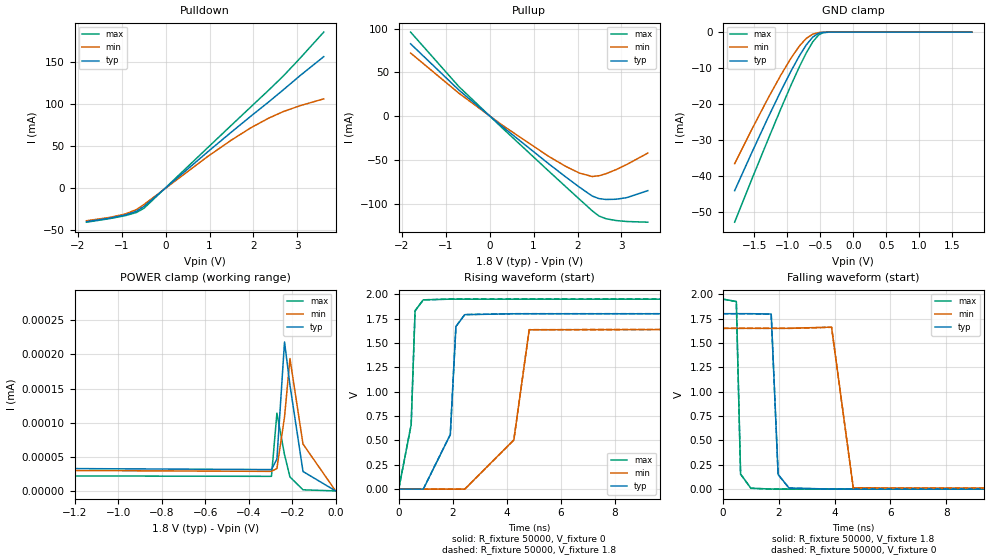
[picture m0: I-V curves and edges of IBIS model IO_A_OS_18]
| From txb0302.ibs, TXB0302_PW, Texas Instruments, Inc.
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[Model]   IO_A_OS_18
Model_type  3-state
Enable   Active-High
Vref =   0
Rref =   50000
Cref =   15p
Vmeas =   0.9
| variable   typ   min   max
C_comp   3.37pF   3.15pF   3.54pF
| C_pullup   1.07pF   0.66pF   1.90pF
| C_pulldown   0.87pF   0.62pF   1.33pF
| C_tri-state   3.37pF   3.15pF   3.54pF
[Temperature Range]   40   100   -40
| Ambient temperature   25   85   -40
[Voltage range]   1.8   1.65   1.95
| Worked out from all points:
|   slope of the pulldown table from 0 to 0.27 V, typ, clamps not added: 22.2 ohm
|   slope of the pullup table from 0 to 0.27 V, typ, clamps not added: 24.2 ohm
|   GND clamp passes 1 mA (typ) near -0.59 V on its own axis
|   rising waveform, R_fixture 50000, V_fixture 0: 20-80 % time 611ps typ, 1.04ns min, 363ps max; typ from 0 V to 1.8 V
|   falling waveform, R_fixture 50000, V_fixture 1.8: 20-80 % time 110ps typ, 174ps min, 69.9ps max; typ from 1.8 V to 0.001 V
|   rising waveform, R_fixture 50000, V_fixture 1.8: 20-80 % time 611ps typ, 1.04ns min, 363ps max; typ from 0.001 V to 1.8 V
|   falling waveform, R_fixture 50000, V_fixture 0: 20-80 % time 110ps typ, 174ps min, 69.9ps max; typ from 1.8 V to 0 V
[GND Clamp]
| IO_A_18
|   Voltage   I(typ)   I(min)   I(max)
-1.8V     -44.03mA   -36.54mA   -52.78mA
-1.53V    -33.08mA   -26.69mA   -40.45mA
-1.295V   -23.82mA   -18.44mA   -29.91mA
-1.1V     -16.42mA   -11.97mA   -21.34mA
-940mV    -10.66mA   -7.1mA     -14.54mA
-815mV    -6.519mA   -3.818mA   -9.525mA
-715mV    -3.614mA   -1.788mA   -5.862mA
-615mV    -1.392mA   -570.2uA   -2.718mA
-525mV    -328.4uA   -135.8uA   -785.2uA
-460mV    -77.79uA   -34.89uA   -182.9uA
-365mV    -6.097uA   -3.221uA   -9.086uA
1.8V      303.3pA    68.73nA    29.48pA
[POWER Clamp]
| IO_A_18
|   Voltage   I(typ)   I(min)   I(max)
-1.8V     249.5nA    33.48nA    134.8uA
-1.78V    136.7nA    32.29nA    68.41uA
-1.755V   74.54nA    31.51nA    24.38uA
-1.665V   35.01nA    30.68nA    329.2nA
-1.63V    33.86nA    30.55nA    73.17nA
-1.575V   33.36nA    30.37nA    22.16nA
-295mV    31.28nA    28.68nA    21.38nA
-270mV    46.7nA     32.91nA    114nA
-235mV    218.3nA    108.2nA    53.04nA
-210mV    155.1nA    194nA      20.51nA
-150mV    28.48nA    68.73nA    1.64nA
0V        0A         0A         0A
[Pulldown]
| IO_A_18
|   Voltage   I(typ)   I(min)   I(max)
-1.8V     -40.22mA   -39.06mA   -40.79mA
-1.27V    -36.02mA   -35.08mA   -36.53mA
-915mV    -32.15mA   -31.06mA   -32.98mA
-665mV    -27.8mA    -25.85mA   -29.28mA
-490mV    -22.01mA   -19.69mA   -24.17mA
955mV     42.66mA    37.19mA    47.63mA
1.5V      66.43mA    56.93mA    74.6mA
1.945V    85.41mA    71.57mA    96.49mA
2.345V    102.1mA    82.86mA    116.1mA
2.68V     116.6mA    90.73mA    133mA
3.06V     133.4mA    97.67mA    154.1mA
3.6V      156mA      105.8mA    185.2mA
[Pullup]
| IO_A_18
|   Voltage   I(typ)   I(min)   I(max)
-1.8V     82.67mA    72.12mA    96.05mA
-700mV    29.78mA    26.2mA     33.72mA
285mV     -11.8mA    -10.27mA   -13.41mA
1.335V    -54.13mA   -45.76mA   -62.36mA
1.73V     -69.43mA   -57.37mA   -80.57mA
2.045V    -81.24mA   -65.1mA    -95.01mA
2.335V    -91.33mA   -69mA      -108.2mA
2.49V     -94.26mA   -68.13mA   -114.2mA
2.645V    -95.23mA   -65.84mA   -117.2mA
2.875V    -94.98mA   -61.17mA   -119.3mA
3.115V    -93.2mA    -55.42mA   -120.4mA
3.6V      -85.14mA   -42.23mA   -121.2mA
[Ramp]
| IO_A_18
| variable   typ   min   max
dV/dt_r   1.09/6.17E-10   1.00/1.06E-09   1.18/3.66E-10
dV/dt_f   1.09/1.24E-10   1.00/1.81E-10   1.18/7.18E-11
R_load = 50000
[Rising Waveform]
| IO_A_18
R_fixture =   50000
C_fixture =   0
L_fixture =   0
V_fixture =   0
V_fixture_min = 0
V_fixture_max = 0
|   Time   V(typ)   V(min)   V(max)
0s        1.766nV    9.766nV    305.3pV
461ps     -8.308uV   11.54nV    661.8mV
605ps     -1.693uV   11.34nV    1.829V
909ps     -128.2uV   -18.95nV   1.942V
1.909ns   559.6mV    -11.58uV   1.949V
2.117ns   1.669V     288.3nV    1.949V
2.445ns   1.79V      24.8uV     1.949V
4.261ns   1.799V     504.7mV    1.949V
4.829ns   1.799V     1.635V     1.949V
36.95ns   1.799V     1.649V     1.949V
[Falling Waveform]
| IO_A_18
R_fixture =   50000
C_fixture =   0
L_fixture =   0
V_fixture =   1.8
V_fixture_min = 1.65
V_fixture_max = 1.95
|   Time   V(typ)   V(min)   V(max)
0s        1.8V       1.65V      1.95V
485ps     1.8V       1.65V      1.925V
637ps     1.8V       1.65V      154.8mV
1.005ns   1.8V       1.65V      9.886mV
1.733ns   1.796V     1.65V      1.189mV
1.981ns   150.6mV    1.65V      994.5uV
2.373ns   11.34mV    1.65V      886.8uV
3.893ns   937.7uV    1.662V     808.4uV
4.669ns   882.2uV    12.78mV    797.8uV
36.95ns   796.3uV    826.6uV    778.1uV
[Rising Waveform]
| IO_A_18
R_fixture =   50000
C_fixture =   0
L_fixture =   0
V_fixture =   1.8
V_fixture_min = 1.65
V_fixture_max = 1.95
|   Time   V(typ)   V(min)   V(max)
0s        795.7uV    821.7uV    777.8uV
461ps     787.4uV    821.7uV    662.7mV
605ps     794uV      821.7uV    1.83V
909ps     667.4uV    821.7uV    1.942V
1.909ns   560.5mV    810.1uV    1.95V
2.117ns   1.669V     822uV      1.95V
2.445ns   1.791V     846.5uV    1.95V
4.261ns   1.8V       505.7mV    1.95V
4.829ns   1.8V       1.636V     1.95V
36.95ns   1.8V       1.65V      1.95V
[Falling Waveform]
| IO_A_18
R_fixture =   50000
C_fixture =   0
L_fixture =   0
V_fixture =   0
V_fixture_min = 0
V_fixture_max = 0
|   Time   V(typ)   V(min)   V(max)
0s        1.799V     1.649V     1.949V
485ps     1.799V     1.649V     1.924V
637ps     1.799V     1.649V     153.9mV
1.005ns   1.799V     1.649V     9.104mV
1.733ns   1.795V     1.649V     410.8uV
1.981ns   149.5mV    1.649V     216.7uV
2.373ns   10.54mV    1.649V     109uV
3.893ns   141.9uV    1.66V      30.64uV
4.669ns   86.48uV    11.95mV    20.03uV
36.95ns   587.3nV    4.835uV    347.2nV
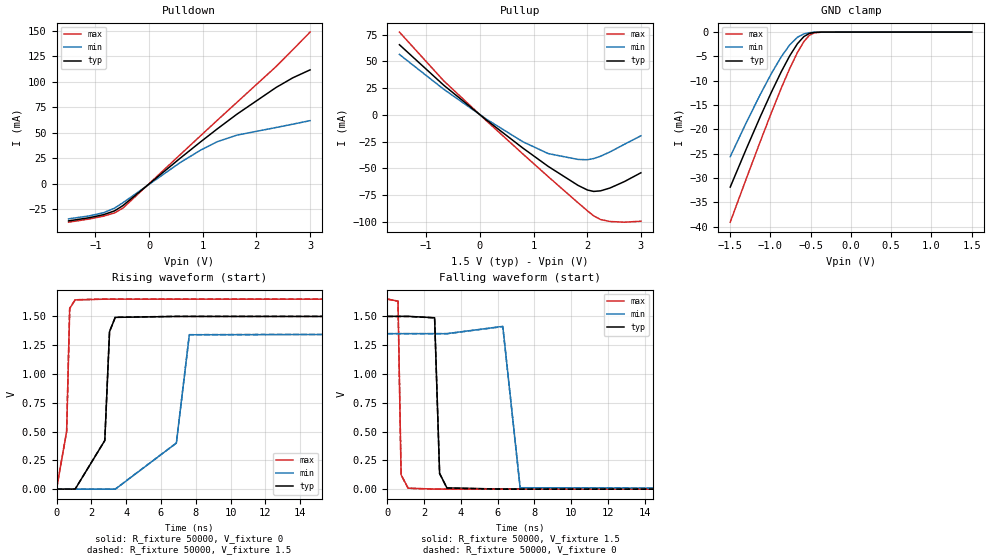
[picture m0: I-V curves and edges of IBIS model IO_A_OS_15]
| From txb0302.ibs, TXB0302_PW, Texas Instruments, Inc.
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[Model]   IO_A_OS_15
Model_type  3-state
Enable   Active-High
Vref =   0
Rref =   50000
Cref =   15p
Vmeas =   0.75
| variable   typ   min   max
C_comp   3.43pF   3.21pF   3.61pF
| C_pullup   1.39pF   0.70pF   3.56pF
| C_pulldown   1.14pF   0.65pF   2.82pF
| C_tri-state   3.43pF   3.21pF   3.61pF
[Temperature Range]   40   100   -40
| Ambient temperature   25   85   -40
[Voltage range]   1.5   1.35   1.65
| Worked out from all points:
|   slope of the pulldown table from 0 to 0.225 V, typ, clamps not added: 22.9 ohm
|   slope of the pullup table from 0 to 0.225 V, typ, clamps not added: 25.2 ohm
|   GND clamp passes 1 mA (typ) near -0.59 V on its own axis
|   rising waveform, R_fixture 50000, V_fixture 0: 20-80 % time 810ps typ, 1.5ns min, 445ps max; typ from 0 V to 1.5 V
|   falling waveform, R_fixture 50000, V_fixture 1.5: 20-80 % time 143ps typ, 229ps min, 82.8ps max; typ from 1.5 V to 0.001 V
|   rising waveform, R_fixture 50000, V_fixture 1.5: 20-80 % time 809ps typ, 1.5ns min, 445ps max; typ from 0.001 V to 1.5 V
|   falling waveform, R_fixture 50000, V_fixture 0: 20-80 % time 144ps typ, 229ps min, 82.8ps max; typ from 1.5 V to 0 V
[GND Clamp]
| IO_A_15
|   Voltage   I(typ)   I(min)   I(max)
-1.5V     -31.88mA   -25.62mA   -39.1mA
-1.3V     -24.01mA   -18.61mA   -30.13mA
-1.13V    -17.53mA   -12.93mA   -22.64mA
-985mV    -12.24mA   -8.412mA   -16.42mA
-865mV    -8.125mA   -5.054mA   -11.49mA
-760mV    -4.86mA    -2.616mA   -7.464mA
-665mV    -2.391mA   -1.068mA   -4.201mA
-585mV    -926.4uA   -370.4uA   -1.947mA
-515mV    -268.3uA   -112.4uA   -649.1uA
-455mV    -68.84uA   -31.05uA   -160.1uA
-365mV    -6.097uA   -3.221uA   -9.086uA
1.5V      240.8pA    68.49nA    22.97pA
[Pulldown]
| IO_A_15
|   Voltage   I(typ)   I(min)   I(max)
-1.5V     -36.25mA   -34.25mA   -37.53mA
-1.115V   -33.16mA   -31.38mA   -34.4mA
-850mV    -30.19mA   -28.26mA   -31.65mA
-645mV    -26.49mA   -23.84mA   -28.47mA
-490mV    -21.38mA   -18.57mA   -23.87mA
575mV     24.88mA    20.65mA    28.32mA
955mV     40.87mA    32.82mA    46.86mA
1.265V    53.54mA    41.09mA    61.89mA
1.635V    68.08mA    47.64mA    79.66mA
2.365V    94.24mA    55.09mA    114.7mA
2.68V     103.8mA    58.4mA     131.3mA
3V        111.5mA    61.85mA    148.5mA
[Pullup]
| IO_A_15
|   Voltage   I(typ)   I(min)   I(max)
-1.5V     65.47mA    56.37mA    77.26mA
-675mV    27.69mA    23.91mA    31.79mA
115mV     -4.573mA   -3.869mA   -5.297mA
800mV     -31.04mA   -25.16mA   -36.54mA
1.275V    -48.25mA   -36.24mA   -57.83mA
1.83V     -65.94mA   -41.69mA   -82.18mA
2.005V    -70.25mA   -41.95mA   -89.69mA
2.12V     -71.57mA   -40.88mA   -94.36mA
2.25V     -71.01mA   -38.63mA   -97.84mA
2.425V    -68.36mA   -34.66mA   -99.65mA
2.69V     -62.45mA   -27.62mA   -100.3mA
3V        -54.16mA   -19.63mA   -99.4mA
[Ramp]
| IO_A_15
| variable   typ   min   max
dV/dt_r   0.91/8.23E-10   0.82/1.52E-09   1.00/4.51E-10
dV/dt_f   0.91/1.62E-10   0.85/2.52E-10   1.00/8.55E-11
R_load = 50000
[Rising Waveform]
| IO_A_15
R_fixture =   50000
C_fixture =   0
L_fixture =   0
V_fixture =   0
V_fixture_min = 0
V_fixture_max = 0
|   Time   V(typ)   V(min)   V(max)
0s        1.769nV    11.6nV     266pV
581ps     297.2nV    11.61nV    501.5mV
757ps     -4.81uV    11.47nV    1.569V
1.069ns   9.363uV    13.26nV    1.643V
2.773ns   422.3mV    552.9nV    1.649V
3.045ns   1.367V     -3.372uV   1.649V
3.373ns   1.491V     -13.23uV   1.649V
6.885ns   1.499V     399.9mV    1.649V
7.629ns   1.499V     1.34V      1.649V
36.52ns   1.499V     1.349V     1.649V
[Falling Waveform]
| IO_A_15
R_fixture =   50000
C_fixture =   0
L_fixture =   0
V_fixture =   1.5
V_fixture_min = 1.35
V_fixture_max = 1.65
|   Time   V(typ)   V(min)   V(max)
0s        1.5V       1.35V      1.65V
581ps     1.5V       1.35V      1.632V
749ps     1.5V       1.35V      124.7mV
1.133ns   1.5V       1.35V      8.456mV
2.573ns   1.488V     1.35V      756.7uV
2.845ns   137mV      1.35V      732.1uV
3.245ns   10.46mV    1.35V      711.9uV
6.285ns   744.6uV    1.413V     674.5uV
7.229ns   732.5uV    12.49mV    671.6uV
36.52ns   684.2uV    726.3uV    666.7uV
[Rising Waveform]
| IO_A_15
R_fixture =   50000
C_fixture =   0
L_fixture =   0
V_fixture =   1.5
V_fixture_min = 1.35
V_fixture_max = 1.65
|   Time   V(typ)   V(min)   V(max)
0s        683.7uV    720.6uV    666.5uV
581ps     684uV      720.6uV    502.3mV
757ps     678.9uV    720.6uV    1.569V
1.069ns   693.1uV    720.6uV    1.644V
2.773ns   423.2mV    721.1uV    1.65V
3.045ns   1.368V     717.2uV    1.65V
3.373ns   1.492V     707.3uV    1.65V
6.885ns   1.5V       400.9mV    1.65V
7.629ns   1.5V       1.341V     1.65V
36.52ns   1.5V       1.35V      1.65V
[Falling Waveform]
| IO_A_15
R_fixture =   50000
C_fixture =   0
L_fixture =   0
V_fixture =   0
V_fixture_min = 0
V_fixture_max = 0
|   Time   V(typ)   V(min)   V(max)
0s        1.499V     1.349V     1.649V
581ps     1.499V     1.349V     1.631V
749ps     1.499V     1.349V     123.9mV
1.133ns   1.499V     1.349V     7.785mV
2.573ns   1.487V     1.349V     90.16uV
2.845ns   136mV      1.349V     65.56uV
3.245ns   9.77mV     1.349V     45.44uV
6.285ns   60.9uV     1.411V     7.989uV
7.229ns   48.83uV    11.73mV    5.084uV
36.52ns   554.1nV    5.699uV    237.9nV
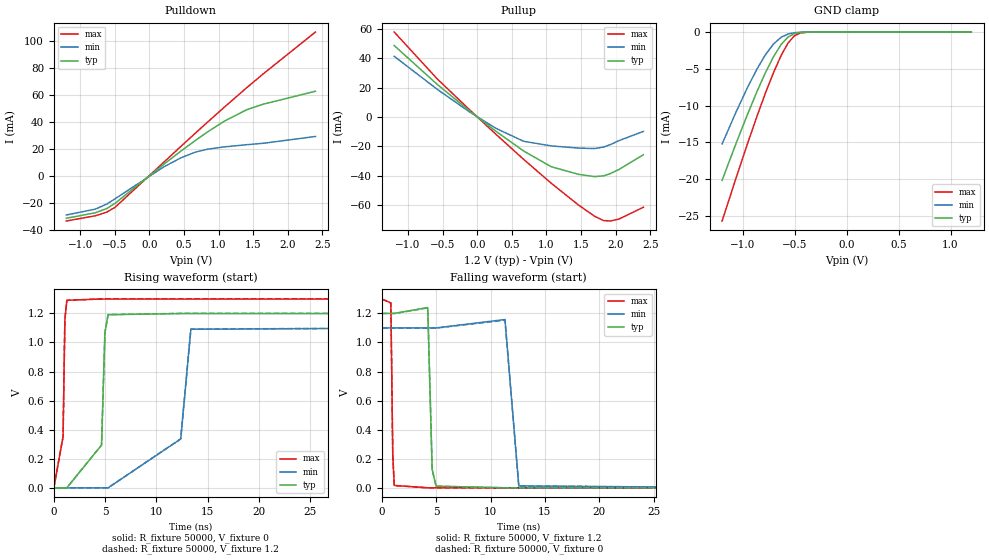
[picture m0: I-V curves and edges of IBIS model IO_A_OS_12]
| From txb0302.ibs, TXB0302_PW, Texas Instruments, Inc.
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[Model]   IO_A_OS_12
Model_type  3-state
Enable   Active-High
Vref =   0
Rref =   50000
Cref =   15p
Vmeas =   0.6
| variable   typ   min   max
C_comp   3.49pF   3.27pF   3.67pF
| C_pullup   2.17pF   0.79pF   5.37pF
| C_pulldown   1.82pF   0.70pF   5.56pF
| C_tri-state   3.49pF   3.27pF   3.67pF
[Temperature Range]   40   100   -40
| Ambient temperature   25   85   -40
[Voltage range]   1.2   1.1   1.3
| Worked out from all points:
|   slope of the pulldown table from 0 to 0.18 V, typ, clamps not added: 24.6 ohm
|   slope of the pullup table from 0 to 0.18 V, typ, clamps not added: 27.5 ohm
|   GND clamp passes 1 mA (typ) near -0.59 V on its own axis
|   rising waveform, R_fixture 50000, V_fixture 0: 20-80 % time 1.24ns typ, 2.4ns min, 639ps max; typ from 0 V to 1.2 V
|   falling waveform, R_fixture 50000, V_fixture 1.2: 20-80 % time 207ps typ, 381ps min, 116ps max; typ from 1.2 V to 0.001 V
|   rising waveform, R_fixture 50000, V_fixture 1.2: 20-80 % time 1.24ns typ, 2.4ns min, 639ps max; typ from 0.001 V to 1.2 V
|   falling waveform, R_fixture 50000, V_fixture 0: 20-80 % time 207ps typ, 382ps min, 116ps max; typ from 1.2 V to 0 V
[GND Clamp]
| IO_A_12
|   Voltage   I(typ)   I(min)   I(max)
-1.2V     -20.17mA   -15.23mA   -25.71mA
-1.07V    -15.31mA   -11.02mA   -20.05mA
-960mV    -11.36mA   -7.676mA   -15.38mA
-865mV    -8.125mA   -5.054mA   -11.49mA
-785mV    -5.598mA   -3.138mA   -8.387mA
-705mV    -3.354mA   -1.626mA   -5.519mA
-630mV    -1.664mA   -696.5uA   -3.14mA
-565mV    -678.3uA   -271.2uA   -1.498mA
-505mV    -217.6uA   -92.4uA    -530uA
-450mV    -60.83uA   -27.6uA    -139.8uA
-365mV    -6.097uA   -3.22uA    -9.086uA
1.2V      188.6pA    17.64nA    18.68pA
[Pulldown]
| IO_A_12
|   Voltage   I(typ)   I(min)   I(max)
-1.2V     -31.51mA   -29.08mA   -33.54mA
-780mV    -27.44mA   -24.75mA   -29.67mA
-615mV    -24.31mA   -20.98mA   -26.96mA
-495mV    -20.42mA   -17.08mA   -23.38mA
205mV     8.337mA    6.418mA    9.812mA
455mV     18.19mA    13.22mA    21.67mA
665mV     26.12mA    17.47mA    31.51mA
840mV     32.4mA     19.62mA    39.63mA
1.08V     40.3mA     21.34mA    50.6mA
1.405V    48.83mA    22.96mA    65.09mA
1.65V     53.03mA    24.04mA    75.62mA
2.4V      62.57mA    29.07mA    106.4mA
[Pullup]
| IO_A_12
|   Voltage   I(typ)   I(min)   I(max)
-1.2V     48.49mA    41.19mA    57.66mA
-580mV    22.19mA    18.85mA    25.93mA
-110mV    4.086mA    3.379mA    4.844mA
270mV     -9.741mA   -7.721mA   -11.76mA
670mV     -23.09mA   -16.51mA   -28.77mA
1.07V     -33.79mA   -19.64mA   -45.04mA
1.465V    -38.96mA   -21.12mA   -59.85mA
1.695V    -40.48mA   -21.45mA   -67.38mA
1.825V    -39.98mA   -20.41mA   -70.31mA
1.925V    -38.38mA   -18.74mA   -70.62mA
2.05V     -35.57mA   -16.02mA   -69.25mA
2.4V      -25.61mA   -9.785mA   -61.26mA
[Ramp]
| IO_A_12
| variable   typ   min   max
dV/dt_r   0.73/1.25E-09   0.67/2.43E-09   0.78/6.46E-10
dV/dt_f   0.75/2.27E-10   0.70/4.12E-10   0.79/1.26E-10
R_load = 50000
[Rising Waveform]
| IO_A_12
R_fixture =   50000
C_fixture =   0
L_fixture =   0
V_fixture =   0
V_fixture_min = 0
V_fixture_max = 0
|   Time   V(typ)   V(min)   V(max)
0s        1.979nV    16.27nV    227.6pV
901ps     434.5nV    16.28nV    352.2mV
1.077ns   479.8nV    16.28nV    1.155V
1.269ns   -1.529uV   16.25nV    1.29V
4.653ns   294.3mV    502nV      1.299V
4.981ns   1.067V     699.6nV    1.299V
5.293ns   1.191V     1.079uV    1.299V
12.37ns   1.199V     336.2mV    1.299V
13.36ns   1.199V     1.091V     1.299V
35.37ns   1.199V     1.099V     1.299V
[Falling Waveform]
| IO_A_12
R_fixture =   50000
C_fixture =   0
L_fixture =   0
V_fixture =   1.2
V_fixture_min = 1.1
V_fixture_max = 1.3
|   Time   V(typ)   V(min)   V(max)
0s        1.2V       1.1V       1.3V
837ps     1.2V       1.1V       1.272V
1.013ns   1.2V       1.1V       233.3mV
1.149ns   1.2V       1.1V       16.32mV
4.229ns   1.24V      1.1V       565.4uV
4.637ns   126.4mV    1.1V       559.8uV
4.997ns   11.55mV    1.1V       556.2uV
11.33ns   611.3uV    1.158V     541.5uV
12.6ns    605.9uV    13.31mV    541.3uV
35.37ns   583.9uV    684uV      540.9uV
[Rising Waveform]
| IO_A_12
R_fixture =   50000
C_fixture =   0
L_fixture =   0
V_fixture =   1.2
V_fixture_min = 1.1
V_fixture_max = 1.3
|   Time   V(typ)   V(min)   V(max)
0s        583.1uV    673.9uV    540.9uV
901ps     583.5uV    673.9uV    352.8mV
1.077ns   583.6uV    673.9uV    1.156V
1.269ns   581.6uV    673.9uV    1.29V
4.653ns   295mV      674.4uV    1.3V
4.981ns   1.068V     674.6uV    1.3V
5.293ns   1.192V     675uV      1.3V
12.37ns   1.2V       337.4mV    1.3V
13.36ns   1.2V       1.092V     1.3V
35.37ns   1.2V       1.1V       1.3V
[Falling Waveform]
| IO_A_12
R_fixture =   50000
C_fixture =   0
L_fixture =   0
V_fixture =   0
V_fixture_min = 0
V_fixture_max = 0
|   Time   V(typ)   V(min)   V(max)
0s        1.199V     1.099V     1.299V
837ps     1.199V     1.099V     1.271V
1.013ns   1.199V     1.099V     232.3mV
1.149ns   1.199V     1.099V     15.75mV
4.229ns   1.238V     1.099V     24.56uV
4.637ns   125.1mV    1.099V     18.94uV
4.997ns   10.94mV    1.099V     15.34uV
11.33ns   28.21uV    1.153V     661.3nV
12.6ns    22.75uV    12.52mV    393.8nV
35.37ns   752.1nV    9.876uV    41.57nV
